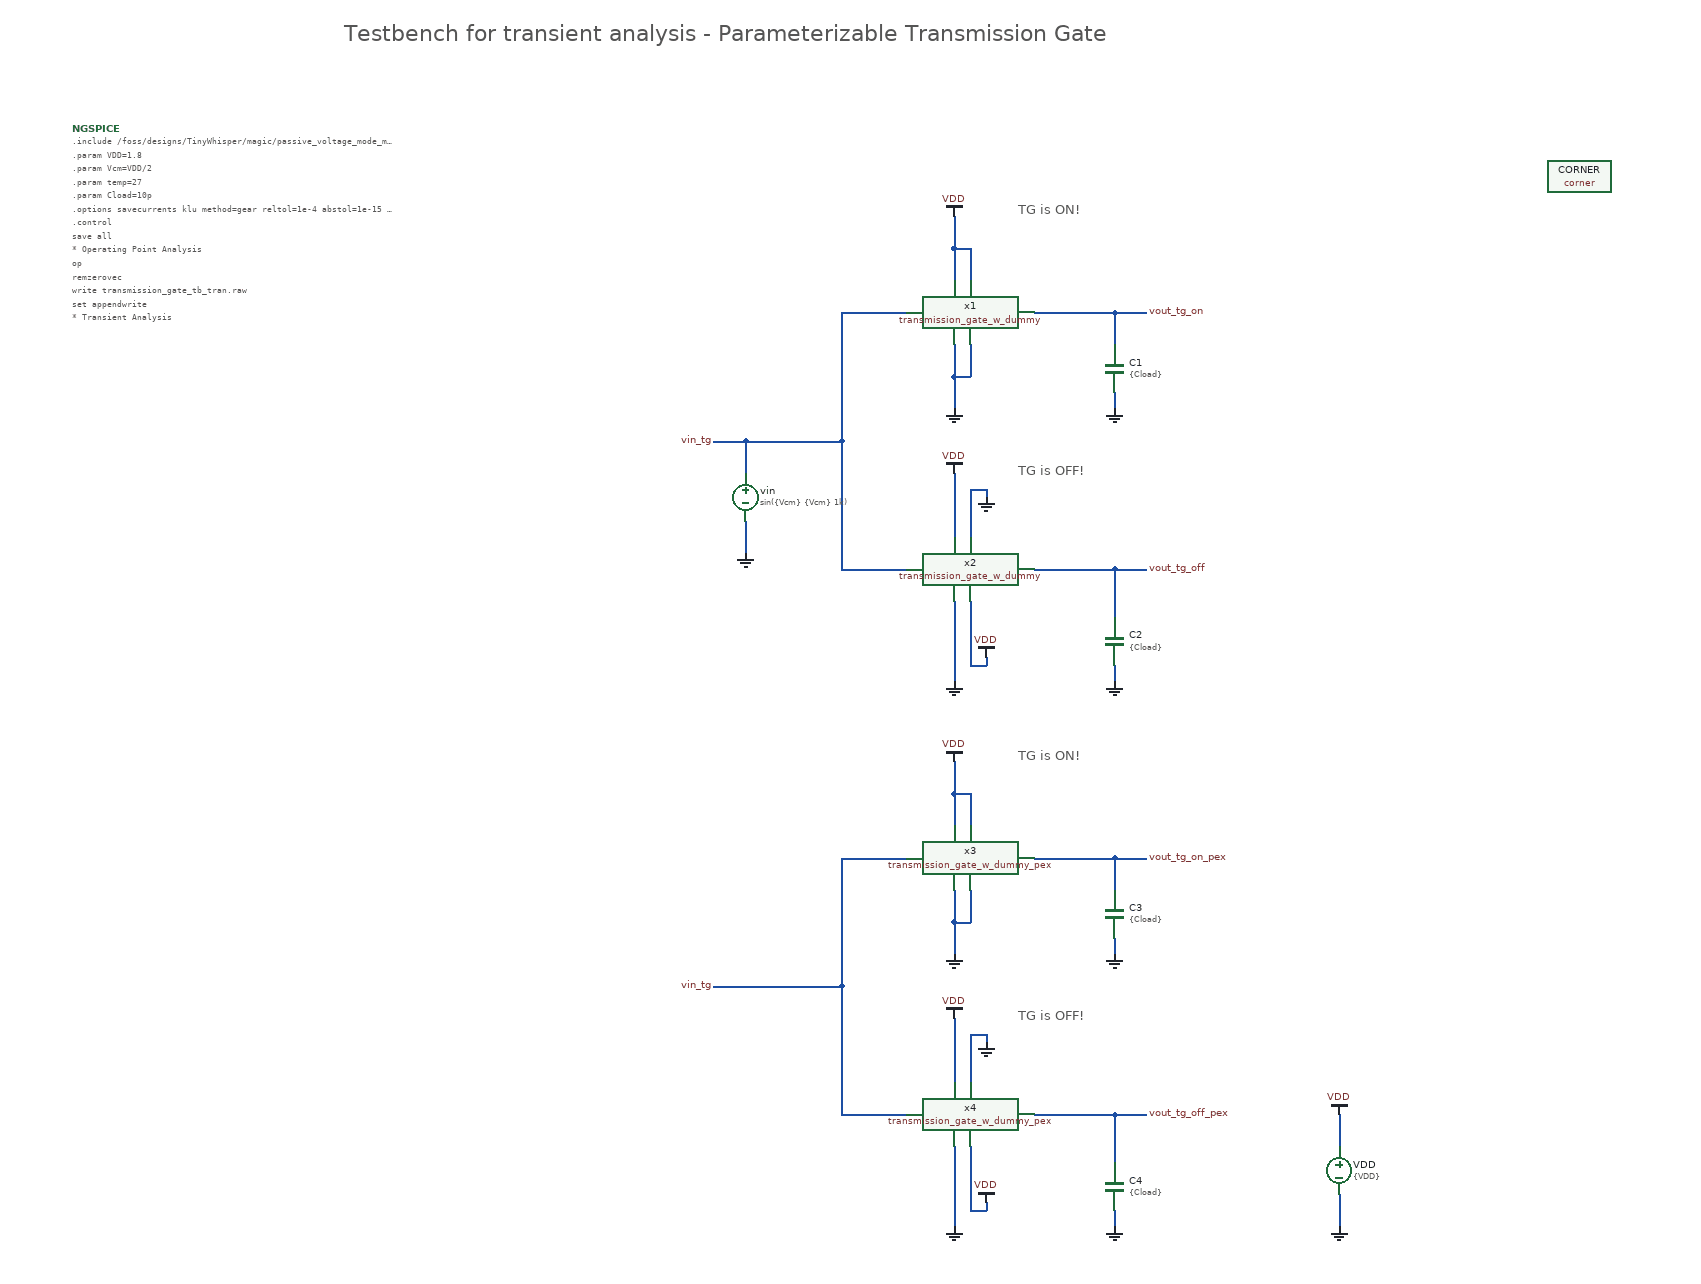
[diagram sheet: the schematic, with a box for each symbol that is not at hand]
v {xschem version=3.4.8RC file_version=1.3}
G {}
K {}
V {}
S {}
F {}
E {}
B 2 1640 -1380 2440 -980 {flags=graph
y1=0.00013
y2=1.8
ypos1=0
ypos2=2
divy=5
subdivy=1
unity=1
x1=0
x2=0.01
divx=5
subdivx=1
xlabmag=1.0
ylabmag=1.0
node="vin_tg
vout_tg_on
vout_tg_on_pex"
color="4 7 12"
dataset=-1
unitx=1
logx=0
logy=0
hilight_wave=-1
linewidth_mult=4}
B 2 1640 -940 2440 -540 {flags=graph
y1=0.00013
y2=1.8
ypos1=0
ypos2=2
divy=5
subdivy=1
unity=1
x1=0
x2=0.01
divx=5
subdivx=1
xlabmag=1.0
ylabmag=1.0
node="vin_tg
vout_tg_off
vout_tg_off_pex"
color="4 7 12"
dataset=-1
unitx=1
logx=0
logy=0
hilight_wave=-1
linewidth_mult=4}
T {Testbench for transient analysis - Parameterizable Transmission Gate} 400 -1720 0 0 1 1 {}
T {TG is ON!} 1240 -1500 0 0 0.5 0.5 {}
T {TG is OFF!} 1240 -1175 0 0 0.5 0.5 {}
T {TG is ON!} 1240 -820 0 0 0.5 0.5 {}
T {TG is OFF!} 1240 -495 0 0 0.5 0.5 {}
N 900 -1200 900 -1160 {
lab=vin_tg}
N 1160 -1160 1160 -1080 {
lab=VDD}
N 1020 -1200 1020 -1040 {
lab=vin_tg}
N 1020 -1360 1020 -1200 {
lab=vin_tg}
N 900 -1200 1020 -1200 {
lab=vin_tg}
N 1360 -1040 1400 -1040 {
lab=vout_tg_off}
N 1160 -1440 1160 -1400 {
lab=VDD}
N 1200 -1140 1200 -1130 {
lab=GND}
N 1180 -1140 1200 -1140 {
lab=GND}
N 1180 -1140 1180 -1080 {
lab=GND}
N 1180 -920 1200 -920 {
lab=VDD}
N 1200 -930 1200 -920 {
lab=VDD}
N 1360 -1360 1400 -1360 {
lab=vout_tg_on}
N 1160 -1440 1180 -1440 {
lab=VDD}
N 1160 -1480 1160 -1440 {
lab=VDD}
N 1180 -1440 1180 -1400 {
lab=VDD}
N 1160 -1280 1160 -1240 {
lab=GND}
N 1180 -1320 1180 -1280 {
lab=GND}
N 1160 -1280 1180 -1280 {
lab=GND}
N 1160 -1320 1160 -1280 {
lab=GND}
N 1180 -1000 1180 -920 {
lab=VDD}
N 1160 -1000 1160 -900 {
lab=GND}
N 900 -1100 900 -1060 {
lab=GND}
N 860 -1200 900 -1200 {
lab=vin_tg}
N 1640 -360 1640 -320 {
lab=VDD}
N 1640 -260 1640 -220 {
lab=GND}
N 1360 -1360 1360 -1320 {
lab=vout_tg_on}
N 1260 -1360 1360 -1360 {
lab=vout_tg_on}
N 1360 -1260 1360 -1240 {
lab=GND}
N 1360 -920 1360 -900 {
lab=GND}
N 1360 -1040 1360 -980 {
lab=vout_tg_off}
N 1260 -1040 1360 -1040 {
lab=vout_tg_off}
N 1020 -1040 1100 -1040 {lab=vin_tg}
N 1020 -1360 1100 -1360 {lab=vin_tg}
N 1160 -480 1160 -400 {
lab=VDD}
N 1020 -520 1020 -360 {
lab=vin_tg}
N 1020 -680 1020 -520 {
lab=vin_tg}
N 900 -520 1020 -520 {
lab=vin_tg}
N 1360 -360 1400 -360 {
lab=vout_tg_off_pex}
N 1160 -760 1160 -720 {
lab=VDD}
N 1200 -460 1200 -450 {
lab=GND}
N 1180 -460 1200 -460 {
lab=GND}
N 1180 -460 1180 -400 {
lab=GND}
N 1180 -240 1200 -240 {
lab=VDD}
N 1200 -250 1200 -240 {
lab=VDD}
N 1360 -680 1400 -680 {
lab=vout_tg_on_pex}
N 1160 -760 1180 -760 {
lab=VDD}
N 1160 -800 1160 -760 {
lab=VDD}
N 1180 -760 1180 -720 {
lab=VDD}
N 1160 -600 1160 -560 {
lab=GND}
N 1180 -640 1180 -600 {
lab=GND}
N 1160 -600 1180 -600 {
lab=GND}
N 1160 -640 1160 -600 {
lab=GND}
N 1180 -320 1180 -240 {
lab=VDD}
N 1160 -320 1160 -220 {
lab=GND}
N 860 -520 900 -520 {
lab=vin_tg}
N 1360 -680 1360 -640 {
lab=vout_tg_on_pex}
N 1260 -680 1360 -680 {
lab=vout_tg_on_pex}
N 1360 -580 1360 -560 {
lab=GND}
N 1360 -240 1360 -220 {
lab=GND}
N 1360 -360 1360 -300 {
lab=vout_tg_off_pex}
N 1260 -360 1360 -360 {
lab=vout_tg_off_pex}
N 1020 -360 1100 -360 {lab=vin_tg}
N 1020 -680 1100 -680 {lab=vin_tg}
C {devices/lab_wire.sym} 1400 -1360 0 1 {name=p1 sig_type=std_logic lab=vout_tg_on}
C {devices/vsource.sym} 1640 -290 0 0 {name=VDD value=\{VDD\}}
C {devices/gnd.sym} 1640 -220 0 0 {name=l6 lab=GND}
C {devices/vdd.sym} 1640 -360 0 0 {name=l8 lab=VDD}
C {devices/vsource.sym} 900 -1130 0 1 {name=vin value="sin(\{Vcm\} \{Vcm\} 1k)"
}
C {devices/gnd.sym} 1160 -1240 0 0 {name=l2 lab=GND}
C {devices/vdd.sym} 1160 -1480 0 0 {name=l4 lab=VDD}
C {devices/lab_wire.sym} 860 -1200 0 0 {name=p2 sig_type=std_logic lab=vin_tg}
C {devices/gnd.sym} 900 -1060 0 0 {name=l1 lab=GND}
C {devices/lab_wire.sym} 1400 -1040 0 1 {name=p3 sig_type=std_logic lab=vout_tg_off}
C {devices/gnd.sym} 1160 -900 0 0 {name=l9 lab=GND}
C {devices/vdd.sym} 1160 -1160 0 0 {name=l11 lab=VDD}
C {devices/gnd.sym} 1200 -1130 0 0 {name=l12 lab=GND}
C {devices/vdd.sym} 1200 -930 0 0 {name=l14 lab=VDD}
C {devices/title-3.sym} 0 0 0 0 {name=l3 author="Simon Dorrer" rev=1.0 lock=true}
C {devices/launcher.sym} 1700 -1550 0 0 {name=h2
descr="Simulate" 
tclcommand="xschem save; xschem netlist; xschem simulate"
}
C {devices/launcher.sym} 1700 -1430 0 0 {name=h1
descr="Load waves" 
tclcommand="xschem raw_read $netlist_dir/transmission_gate_tb_tran.raw tran"
}
C {devices/launcher.sym} 1700 -1490 0 0 {name=h3
descr="Annotate OP" 
tclcommand="set show_hidden_texts 1; xschem annotate_op"
}
C {code_shown.sym} 60 -1590 0 0 {name=NGSPICE
only_toplevel=true
value="
.include /foss/designs/TinyWhisper/magic/passive_voltage_mode_mixer/transmission_gate_w_dummy/transmission_gate_w_dummy_pex.spice
.param VDD=1.8
.param Vcm=VDD/2
.param temp=27
.param Cload=10p
.options savecurrents klu method=gear reltol=1e-4 abstol=1e-15 gmin=1e-15
.control

save all

* Operating Point Analysis
op
remzerovec
write transmission_gate_tb_tran.raw
set appendwrite

* Transient Analysis
tran 50u 50ms
write transmission_gate_tb_tran.raw

plot vin_tg vout_tg_on vout_tg_on_pex
plot vin_tg vout_tg_off vout_tg_off_pex


*quit
.endc"}
C {devices/capa.sym} 1360 -1290 0 0 {name=C1
m=1
value=\{Cload\}
footprint=1206
device="ceramic capacitor"}
C {devices/capa.sym} 1360 -950 0 0 {name=C2
m=1
value=\{Cload\}
footprint=1206
device="ceramic capacitor"}
C {devices/gnd.sym} 1360 -900 0 0 {name=l5 lab=GND}
C {devices/gnd.sym} 1360 -1240 0 0 {name=l7 lab=GND}
C {sky130_fd_pr/corner.sym} 1940 -1530 0 0 {name=CORNER only_toplevel=false corner=tt}
C {transmission_gate_w_dummy.sym} 1180 -1360 0 0 {name=x1}
C {transmission_gate_w_dummy.sym} 1180 -1040 0 0 {name=x2}
C {devices/lab_wire.sym} 1400 -680 0 1 {name=p4 sig_type=std_logic lab=vout_tg_on_pex}
C {devices/gnd.sym} 1160 -560 0 0 {name=l10 lab=GND}
C {devices/vdd.sym} 1160 -800 0 0 {name=l13 lab=VDD}
C {devices/lab_wire.sym} 860 -520 0 0 {name=p5 sig_type=std_logic lab=vin_tg}
C {devices/lab_wire.sym} 1400 -360 0 1 {name=p6 sig_type=std_logic lab=vout_tg_off_pex}
C {devices/gnd.sym} 1160 -220 0 0 {name=l16 lab=GND}
C {devices/vdd.sym} 1160 -480 0 0 {name=l17 lab=VDD}
C {devices/gnd.sym} 1200 -450 0 0 {name=l18 lab=GND}
C {devices/vdd.sym} 1200 -250 0 0 {name=l19 lab=VDD}
C {devices/capa.sym} 1360 -610 0 0 {name=C3
m=1
value=\{Cload\}
footprint=1206
device="ceramic capacitor"}
C {devices/capa.sym} 1360 -270 0 0 {name=C4
m=1
value=\{Cload\}
footprint=1206
device="ceramic capacitor"}
C {devices/gnd.sym} 1360 -220 0 0 {name=l20 lab=GND}
C {devices/gnd.sym} 1360 -560 0 0 {name=l21 lab=GND}
C {transmission_gate_w_dummy_pex.sym} 1180 -680 0 0 {name=x3}
C {transmission_gate_w_dummy_pex.sym} 1180 -360 0 0 {name=x4}
